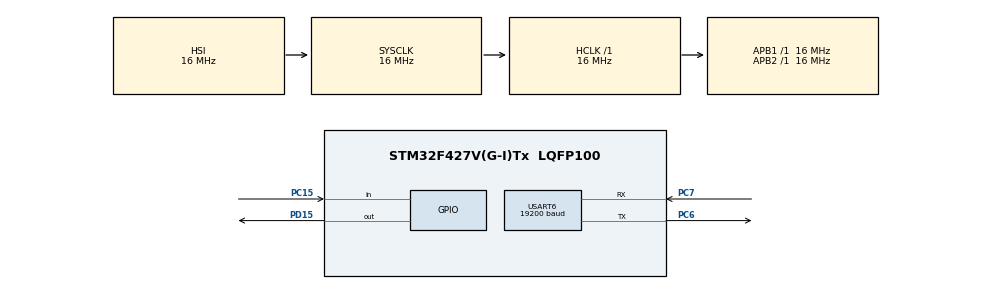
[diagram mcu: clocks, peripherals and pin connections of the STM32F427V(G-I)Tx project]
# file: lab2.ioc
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Mcu.Family=STM32F4
Mcu.Name=STM32F427V(G-I)Tx
Mcu.Package=LQFP100
NVIC.PriorityGroup=NVIC_PRIORITYGROUP_4
NVIC.USART6_IRQn=true\:0\:0\:false\:false\:true\:true\:true\:true
PA13.Mode=JTAG_5_pins
PA13.Signal=SYS_JTMS-SWDIO
PA14.Mode=JTAG_5_pins
PA14.Signal=SYS_JTCK-SWCLK
PA15.Mode=JTAG_5_pins
PA15.Signal=SYS_JTDI
PB3.Mode=JTAG_5_pins
PB3.Signal=SYS_JTDO-SWO
PB4.Mode=JTAG_5_pins
PB4.Signal=SYS_JTRST
PC15/OSC32_OUT.Signal=GPIO_Input
PC6.Mode=Asynchronous
PC6.Signal=USART6_TX
PC7.Mode=Asynchronous
PC7.Signal=USART6_RX
PD15.Signal=GPIO_Output
ProjectManager.HeapSize=0x200
ProjectManager.StackSize=0x400
ProjectManager.TargetToolchain=STM32CubeIDE
RCC.AHBFreq_Value=16000000
RCC.APB1Freq_Value=16000000
RCC.APB2Freq_Value=16000000
RCC.CortexFreq_Value=16000000
RCC.HSE_VALUE=25000000
RCC.HSI_VALUE=16000000
RCC.LSE_VALUE=32768
RCC.SYSCLKFreq_VALUE=16000000
RCC.VCOOutputFreq_Value=192000000
USART6.BaudRate=19200
USART6.VirtualMode=VM_ASYNC
board=custom

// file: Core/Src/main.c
/* USER CODE BEGIN Header */
/**
  ******************************************************************************
  * @file           : main.c
  * @brief          : Main program body
  ******************************************************************************
  * @attention
  *
  * <h2><center>&copy; Copyright (c) 2023 STMicroelectronics.
  * All rights reserved.</center></h2>
  *
  * This software component is licensed by ST under BSD 3-Clause license,
  * the "License"; You may not use this file except in compliance with the
  * License. You may obtain a copy of the License at:
  *                        opensource.org/licenses/BSD-3-Clause
  *
  ******************************************************************************
  */
/* USER CODE END Header */
#include "main.h"

/* USER CODE BEGIN Includes */
#include "uart.h"
#include "btn.h"
#include <stdbool.h>
#include <stdint.h>
#include <stdio.h>
/* USER CODE END Includes */

UART_HandleTypeDef huart6;

void SystemClock_Config(void);
static void MX_GPIO_Init(void);
static void MX_USART6_UART_Init(void);

typedef enum {
	READ_NUM1,
	READ_NUM2,
	CALC_WRITE
} CalcState;

typedef enum {
	PLUS,
	MINUS,
	MUL,
	DIV
} Operation;

int main(void)
{

  /* MCU Configuration--------------------------------------------------------*/

  /* Reset of all peripherals, Initializes the Flash interface and the Systick. */
  HAL_Init();

  /* Configure the system clock */
  SystemClock_Config();

  /* Initialize all configured peripherals */
  MX_GPIO_Init();
  MX_USART6_UART_Init();
  /* USER CODE BEGIN 2 */
  UART_Init(&huart6);
  UART_Set_Mode(INT_DISABLE);
  /* USER CODE END 2 */

  /* Infinite loop */
  /* USER CODE BEGIN WHILE */
  unsigned char input;
  char res_string[64];
  CalcState cur_state = READ_NUM1;
  CalcState next_state = READ_NUM1;
  int16_t num1 = 0;
  int16_t num2 = 0;
  Operation op;
  UART_Mode uart_mode = INT_DISABLE;
  UART_Ret_Code status;
  unsigned int digits_read = 0;
  int16_t result = 0;
  UART_Send_Data((uint8_t*)"Hail!\n\r", 7);
  bool error = false;
  while (1)
  {
	enum ButtonState btn = Get_Button_State();
	if (btn != NONE) {
		next_state = READ_NUM1;
		num1 = 0;
		num2 = 0;
		digits_read = 0;
		uart_mode = uart_mode == INT_DISABLE ? INT_ENABLE : INT_DISABLE;
		UART_Set_Mode(uart_mode);
		int l = sprintf(res_string, "Mode was switched to %s\n\r", uart_mode == INT_DISABLE ? "INT_DISABLE" : "INT_ENABLE");
		UART_Send_Data((uint8_t*)res_string, l);

	}
    switch (cur_state) {
    case READ_NUM1:
    	status = UART_Read_Data(&input, 1);
    	if (status != UART_SUCCESS) {
    		next_state = READ_NUM1;
    		break;
    	}
    	if ('0' <= input && input <= '9') {
    		next_state = READ_NUM1;
    		++digits_read;
    		if (digits_read > 5) {
    			break;
    		}
    	    UART_Send_Data(&input, 1);
    		num1 = num1 * 10 + (input - '0');
    	}
    	if (input == '+' && digits_read > 0) {
    		op = PLUS;
    		next_state = READ_NUM2;
    		UART_Send_Data(&input, 1);
    	}
    	if (input == '-' && digits_read > 0) {
    		op = MINUS;
    		next_state = READ_NUM2;
    		UART_Send_Data(&input, 1);
    	}
    	if (input == '*' && digits_read > 0) {
    		op = MUL;
    		next_state = READ_NUM2;
    		UART_Send_Data(&input, 1);
    	}
    	if (input == '/' && digits_read > 0) {
    		op = DIV;
			next_state = READ_NUM2;
			UART_Send_Data(&input, 1);
    	}
    	break;
    case READ_NUM2:
		status = UART_Read_Data(&input, 1);
		if (status != UART_SUCCESS) {
			next_state = READ_NUM2;
			break;
		}
		if ('0' <= input && input <= '9') {
			next_state = READ_NUM2;
			++digits_read;
			if (digits_read > 5) {
				break;
			}
			UART_Send_Data(&input, 1);
			num2 = num2 * 10 + (input - '0');
		}
		if (input == '=' && digits_read > 0) {
			next_state = CALC_WRITE;
			UART_Send_Data(&input, 1);
		}
		break;
    case CALC_WRITE:
    	if (num1 < 0 || num2 < 0) {
    		error = true;
    	}
    	switch (op) {
    	case PLUS:
    		result = num1 + num2;
    		if (result < 0) {
    			error = true;
    		}
    		break;
    	case MINUS:
    		result = num1 - num2;
    		if ((num1 > num2 && result < 0) || (num1 < num2 && result > 0)) {
    			error = true;
    		}
    		break;
    	case MUL:
    		result = num1 * num2;
    		if (result < 0) {
    			error = true;
    		}
    		break;
    	case DIV:
    		if (num2 == 0) {
    			error = true;
    		}
    		result = num1 / num2;
    		break;
    	}
    	int l = error ? sprintf(res_string, "error!\n\r") : sprintf(res_string, "%d\n\r", result);
    	while (UART_Get_State() == BUSY_SENDING);
    	UART_Send_Data((uint8_t*)res_string, l);
    	next_state = READ_NUM1;
    	if (error) {
    		HAL_GPIO_WritePin(GPIOD, GPIO_PIN_15, GPIO_PIN_SET);
    		HAL_Delay(1000);
    		HAL_GPIO_WritePin(GPIOD, GPIO_PIN_15, GPIO_PIN_RESET);
    	}
    	error = false;
    	num1 = 0;
    	num2 = 0;
    }
    if (cur_state != next_state) {
    	digits_read = 0;
    	cur_state = next_state;
    }
    /* USER CODE END WHILE */

  }
}

void SystemClock_Config(void)
{
  RCC_OscInitTypeDef RCC_OscInitStruct = {0};
  RCC_ClkInitTypeDef RCC_ClkInitStruct = {0};

  /** Configure the main internal regulator output voltage
  */
  __HAL_RCC_PWR_CLK_ENABLE();
  __HAL_PWR_VOLTAGESCALING_CONFIG(PWR_REGULATOR_VOLTAGE_SCALE3);
  /** Initializes the RCC Oscillators according to the specified parameters
  * in the RCC_OscInitTypeDef structure.
  */
  RCC_OscInitStruct.OscillatorType = RCC_OSCILLATORTYPE_HSI;
  RCC_OscInitStruct.HSIState = RCC_HSI_ON;
  RCC_OscInitStruct.HSICalibrationValue = RCC_HSICALIBRATION_DEFAULT;
  RCC_OscInitStruct.PLL.PLLState = RCC_PLL_NONE;
  if (HAL_RCC_OscConfig(&RCC_OscInitStruct) != HAL_OK)
  {
    Error_Handler();
  }
  /** Initializes the CPU, AHB and APB buses clocks
  */
  RCC_ClkInitStruct.ClockType = RCC_CLOCKTYPE_HCLK|RCC_CLOCKTYPE_SYSCLK
                              |RCC_CLOCKTYPE_PCLK1|RCC_CLOCKTYPE_PCLK2;
  RCC_ClkInitStruct.SYSCLKSource = RCC_SYSCLKSOURCE_HSI;
  RCC_ClkInitStruct.AHBCLKDivider = RCC_SYSCLK_DIV1;
  RCC_ClkInitStruct.APB1CLKDivider = RCC_HCLK_DIV1;
  RCC_ClkInitStruct.APB2CLKDivider = RCC_HCLK_DIV1;

  if (HAL_RCC_ClockConfig(&RCC_ClkInitStruct, FLASH_LATENCY_0) != HAL_OK)
  {
    Error_Handler();
  }
}

static void MX_USART6_UART_Init(void)
{

  huart6.Instance = USART6;
  huart6.Init.BaudRate = 19200;
  huart6.Init.WordLength = UART_WORDLENGTH_8B;
  huart6.Init.StopBits = UART_STOPBITS_1;
  huart6.Init.Parity = UART_PARITY_NONE;
  huart6.Init.Mode = UART_MODE_TX_RX;
  huart6.Init.HwFlowCtl = UART_HWCONTROL_NONE;
  huart6.Init.OverSampling = UART_OVERSAMPLING_16;
  if (HAL_UART_Init(&huart6) != HAL_OK)
  {
    Error_Handler();
  }

}

static void MX_GPIO_Init(void)
{
  GPIO_InitTypeDef GPIO_InitStruct = {0};

  /* GPIO Ports Clock Enable */
  __HAL_RCC_GPIOC_CLK_ENABLE();
  __HAL_RCC_GPIOD_CLK_ENABLE();
  __HAL_RCC_GPIOA_CLK_ENABLE();
  __HAL_RCC_GPIOB_CLK_ENABLE();

  /*Configure GPIO pin Output Level */
  HAL_GPIO_WritePin(GPIOD, GPIO_PIN_13|GPIO_PIN_14|GPIO_PIN_15, GPIO_PIN_RESET);

  /*Configure GPIO pin : PC15 */
  GPIO_InitStruct.Pin = GPIO_PIN_15;
  GPIO_InitStruct.Mode = GPIO_MODE_INPUT;
  GPIO_InitStruct.Pull = GPIO_NOPULL;
  HAL_GPIO_Init(GPIOC, &GPIO_InitStruct);

  /*Configure GPIO pins : PD13 PD14 PD15 */
  GPIO_InitStruct.Pin = GPIO_PIN_13|GPIO_PIN_14|GPIO_PIN_15;
  GPIO_InitStruct.Mode = GPIO_MODE_OUTPUT_PP;
  GPIO_InitStruct.Pull = GPIO_NOPULL;
  GPIO_InitStruct.Speed = GPIO_SPEED_FREQ_LOW;
  HAL_GPIO_Init(GPIOD, &GPIO_InitStruct);

}

void Error_Handler(void)
{
  __disable_irq();
  while (1)
  {
  }
}

/************************ (C) COPYRIGHT STMicroelectronics *****END OF FILE****/
